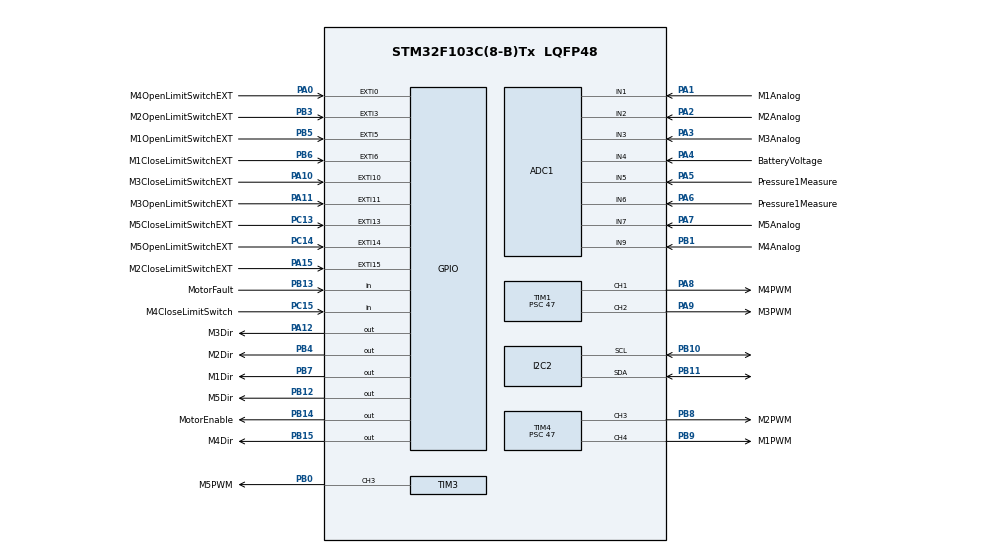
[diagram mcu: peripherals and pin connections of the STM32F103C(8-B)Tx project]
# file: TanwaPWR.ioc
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ADC1.Channel-0\#ChannelRegularConversion=ADC_CHANNEL_1
ADC1.Channel-1\#ChannelRegularConversion=ADC_CHANNEL_2
ADC1.Channel-2\#ChannelRegularConversion=ADC_CHANNEL_3
ADC1.Channel-3\#ChannelRegularConversion=ADC_CHANNEL_4
ADC1.Channel-4\#ChannelRegularConversion=ADC_CHANNEL_5
ADC1.Channel-5\#ChannelRegularConversion=ADC_CHANNEL_6
ADC1.Channel-6\#ChannelRegularConversion=ADC_CHANNEL_7
ADC1.Channel-7\#ChannelRegularConversion=ADC_CHANNEL_9
ADC1.ContinuousConvMode=ENABLE
ADC1.DiscontinuousConvMode=DISABLE
ADC1.NbrOfConversion=8
ADC1.NbrOfConversionFlag=1
ADC1.Rank-0\#ChannelRegularConversion=1
ADC1.Rank-1\#ChannelRegularConversion=2
ADC1.Rank-2\#ChannelRegularConversion=3
ADC1.Rank-3\#ChannelRegularConversion=4
ADC1.Rank-4\#ChannelRegularConversion=5
ADC1.Rank-5\#ChannelRegularConversion=6
ADC1.Rank-6\#ChannelRegularConversion=7
ADC1.Rank-7\#ChannelRegularConversion=8
ADC1.SamplingTime-0\#ChannelRegularConversion=ADC_SAMPLETIME_28CYCLES_5
ADC1.SamplingTime-1\#ChannelRegularConversion=ADC_SAMPLETIME_28CYCLES_5
ADC1.SamplingTime-2\#ChannelRegularConversion=ADC_SAMPLETIME_28CYCLES_5
ADC1.SamplingTime-3\#ChannelRegularConversion=ADC_SAMPLETIME_28CYCLES_5
ADC1.SamplingTime-4\#ChannelRegularConversion=ADC_SAMPLETIME_28CYCLES_5
ADC1.SamplingTime-5\#ChannelRegularConversion=ADC_SAMPLETIME_28CYCLES_5
ADC1.SamplingTime-6\#ChannelRegularConversion=ADC_SAMPLETIME_28CYCLES_5
ADC1.SamplingTime-7\#ChannelRegularConversion=ADC_SAMPLETIME_28CYCLES_5
ADC1.master=1
Dma.ADC1.1.Direction=DMA_PERIPH_TO_MEMORY
Dma.ADC1.1.Instance=DMA1_Channel1
Dma.ADC1.1.MemDataAlignment=DMA_MDATAALIGN_HALFWORD
Dma.ADC1.1.MemInc=DMA_MINC_ENABLE
Dma.ADC1.1.Mode=DMA_CIRCULAR
Dma.ADC1.1.PeriphDataAlignment=DMA_PDATAALIGN_HALFWORD
Dma.ADC1.1.PeriphInc=DMA_PINC_DISABLE
Dma.ADC1.1.Priority=DMA_PRIORITY_MEDIUM
Dma.I2C2_TX.0.Direction=DMA_MEMORY_TO_PERIPH
Dma.I2C2_TX.0.Instance=DMA1_Channel4
Dma.I2C2_TX.0.MemDataAlignment=DMA_MDATAALIGN_BYTE
Dma.I2C2_TX.0.MemInc=DMA_MINC_ENABLE
Dma.I2C2_TX.0.Mode=DMA_NORMAL
Dma.I2C2_TX.0.PeriphDataAlignment=DMA_PDATAALIGN_BYTE
Dma.I2C2_TX.0.PeriphInc=DMA_PINC_DISABLE
Dma.I2C2_TX.0.Priority=DMA_PRIORITY_HIGH
Dma.Request0=I2C2_TX
Dma.Request1=ADC1
FREERTOS.Tasks01=COM,24,128,TaskCOM,Default,NULL,Dynamic,NULL,NULL;Valves,16,128,TaskValves,Default,NULL,Dynamic,NULL,NULL;Measure,8,128,TaskMeasure,Default,NULL,Dynamic,NULL,NULL
FREERTOS.configUSE_NEWLIB_REENTRANT=0
I2C2.OwnAddress=26
Mcu.Family=STM32F1
Mcu.Name=STM32F103C(8-B)Tx
Mcu.Package=LQFP48
NVIC.DMA1_Channel1_IRQn=true\:5\:0\:false\:false\:true\:true\:false\:true
NVIC.DMA1_Channel4_IRQn=true\:5\:0\:false\:false\:true\:true\:false\:true
NVIC.EXTI15_10_IRQn=true\:5\:0\:false\:false\:true\:true\:true\:true
NVIC.EXTI3_IRQn=true\:5\:0\:false\:false\:true\:true\:true\:true
NVIC.EXTI9_5_IRQn=true\:5\:0\:false\:false\:true\:true\:true\:true
NVIC.I2C2_EV_IRQn=true\:5\:0\:false\:false\:true\:true\:true\:true
NVIC.PriorityGroup=NVIC_PRIORITYGROUP_4
NVIC.TIM2_IRQn=true\:15\:0\:false\:false\:true\:false\:false\:true
NVIC.TimeBase=TIM2_IRQn
NVIC.TimeBaseIP=TIM2
PA0-WKUP.GPIO_Label=M4OpenLimitSwitchEXT
PA0-WKUP.GPIO_ModeDefaultEXTI=GPIO_MODE_IT_FALLING
PA0-WKUP.GPIO_PuPd=GPIO_PULLUP
PA0-WKUP.Signal=GPXTI0
PA1.GPIO_Label=M1Analog
PA1.Signal=ADCx_IN1
PA10.GPIO_Label=M3CloseLimitSwitchEXT
PA10.GPIO_ModeDefaultEXTI=GPIO_MODE_IT_FALLING
PA10.GPIO_PuPd=GPIO_PULLUP
PA10.Signal=GPXTI10
PA11.GPIO_Label=M3OpenLimitSwitchEXT
PA11.GPIO_ModeDefaultEXTI=GPIO_MODE_IT_FALLING
PA11.GPIO_PuPd=GPIO_PULLUP
PA11.Signal=GPXTI11
PA12.GPIO_Label=M3Dir
PA12.Signal=GPIO_Output
PA13.Mode=Serial_Wire
PA13.Signal=SYS_JTMS-SWDIO
PA14.Mode=Serial_Wire
PA14.Signal=SYS_JTCK-SWCLK
PA15.GPIO_Label=M2CloseLimitSwitchEXT
PA15.GPIO_ModeDefaultEXTI=GPIO_MODE_IT_FALLING
PA15.GPIO_PuPd=GPIO_PULLUP
PA15.Signal=GPXTI15
PA2.GPIO_Label=M2Analog
PA2.Signal=ADCx_IN2
PA3.GPIO_Label=M3Analog
PA3.Signal=ADCx_IN3
PA4.GPIO_Label=BatteryVoltage
PA4.Signal=ADCx_IN4
PA5.GPIO_Label=Pressure1Measure
PA5.Signal=ADCx_IN5
PA6.GPIO_Label=Pressure1Measure
PA6.Signal=ADCx_IN6
PA7.GPIO_Label=M5Analog
PA7.Signal=ADCx_IN7
PA8.GPIO_Label=M4PWM
PA8.Signal=S_TIM1_CH1
PA9.GPIO_Label=M3PWM
PA9.Signal=S_TIM1_CH2
PB0.GPIO_Label=M5PWM
PB0.Signal=S_TIM3_CH3
PB1.GPIO_Label=M4Analog
PB1.Signal=ADCx_IN9
PB10.Mode=I2C
PB10.Signal=I2C2_SCL
PB11.Mode=I2C
PB11.Signal=I2C2_SDA
PB12.GPIO_Label=M5Dir
PB12.Signal=GPIO_Output
PB13.GPIO_Label=MotorFault
PB13.Signal=GPIO_Input
PB14.GPIO_Label=MotorEnable
PB14.GPIO_PuPd=GPIO_NOPULL
PB14.Signal=GPIO_Output
PB15.GPIO_Label=M4Dir
PB15.Signal=GPIO_Output
PB3.GPIO_Label=M2OpenLimitSwitchEXT
PB3.GPIO_ModeDefaultEXTI=GPIO_MODE_IT_FALLING
PB3.GPIO_PuPd=GPIO_PULLUP
PB3.Signal=GPXTI3
PB4.GPIO_Label=M2Dir
PB4.Signal=GPIO_Output
PB5.GPIO_Label=M1OpenLimitSwitchEXT
PB5.GPIO_ModeDefaultEXTI=GPIO_MODE_IT_FALLING
PB5.GPIO_PuPd=GPIO_PULLUP
PB5.Signal=GPXTI5
PB6.GPIO_Label=M1CloseLimitSwitchEXT
PB6.GPIO_ModeDefaultEXTI=GPIO_MODE_IT_FALLING
PB6.GPIO_PuPd=GPIO_PULLUP
PB6.Signal=GPXTI6
PB7.GPIO_Label=M1Dir
PB7.Signal=GPIO_Output
PB8.GPIO_Label=M2PWM
PB8.Signal=S_TIM4_CH3
PB9.GPIO_Label=M1PWM
PB9.Signal=S_TIM4_CH4
PC13-TAMPER-RTC.GPIO_Label=M5CloseLimitSwitchEXT
PC13-TAMPER-RTC.GPIO_ModeDefaultEXTI=GPIO_MODE_IT_FALLING
PC13-TAMPER-RTC.GPIO_PuPd=GPIO_PULLUP
PC13-TAMPER-RTC.Signal=GPXTI13
PC14-OSC32_IN.GPIO_Label=M5OpenLimitSwitchEXT
PC14-OSC32_IN.GPIO_ModeDefaultEXTI=GPIO_MODE_IT_FALLING
PC14-OSC32_IN.GPIO_PuPd=GPIO_PULLUP
PC14-OSC32_IN.Signal=GPXTI14
PC15-OSC32_OUT.GPIO_Label=M4CloseLimitSwitch
PC15-OSC32_OUT.GPIO_PuPd=GPIO_PULLUP
PC15-OSC32_OUT.Signal=GPIO_Input
PD0-OSC_IN.Mode=HSE-External-Oscillator
PD0-OSC_IN.Signal=RCC_OSC_IN
PD1-OSC_OUT.Mode=HSE-External-Oscillator
PD1-OSC_OUT.Signal=RCC_OSC_OUT
ProjectManager.HeapSize=0x200
ProjectManager.StackSize=0x400
ProjectManager.TargetToolchain=STM32CubeIDE
RCC.ADCPresc=RCC_ADCPCLK2_DIV4
RCC.AHBFreq_Value=48000000
RCC.APB1CLKDivider=RCC_HCLK_DIV2
RCC.APB1Freq_Value=24000000
RCC.APB1TimFreq_Value=48000000
RCC.APB2CLKDivider=RCC_HCLK_DIV2
RCC.APB2Freq_Value=24000000
RCC.APB2TimFreq_Value=48000000
RCC.HCLKFreq_Value=48000000
RCC.PLLMUL=RCC_PLL_MUL6
RCC.PLLSourceVirtual=RCC_PLLSOURCE_HSE
RCC.SYSCLKFreq_VALUE=48000000
RCC.SYSCLKSource=RCC_SYSCLKSOURCE_PLLCLK
RCC.USBFreq_Value=48000000
SH.ADCx_IN1.0=ADC1_IN1,IN1
SH.ADCx_IN2.0=ADC1_IN2,IN2
SH.ADCx_IN3.0=ADC1_IN3,IN3
SH.ADCx_IN4.0=ADC1_IN4,IN4
SH.ADCx_IN5.0=ADC1_IN5,IN5
SH.ADCx_IN6.0=ADC1_IN6,IN6
SH.ADCx_IN7.0=ADC1_IN7,IN7
SH.ADCx_IN9.0=ADC1_IN9,IN9
SH.S_TIM1_CH1.0=TIM1_CH1,PWM Generation1 CH1
SH.S_TIM1_CH2.0=TIM1_CH2,PWM Generation2 CH2
SH.S_TIM3_CH3.0=TIM3_CH3,PWM Generation3 CH3
SH.S_TIM4_CH3.0=TIM4_CH3,PWM Generation3 CH3
SH.S_TIM4_CH4.0=TIM4_CH4,PWM Generation4 CH4
TIM1.AutoReloadPreload=TIM_AUTORELOAD_PRELOAD_ENABLE
TIM1.Channel-PWM\ Generation1\ CH1=TIM_CHANNEL_1
TIM1.Channel-PWM\ Generation2\ CH2=TIM_CHANNEL_2
TIM1.OCMode_PWM-PWM\ Generation2\ CH2=TIM_OCMODE_PWM1
TIM1.Period=999
TIM1.Prescaler=47
TIM1.Pulse-PWM\ Generation1\ CH1=1000
TIM1.Pulse-PWM\ Generation2\ CH2=1000
TIM3.AutoReloadPreload=TIM_AUTORELOAD_PRELOAD_ENABLE
TIM3.Channel-PWM\ Generation3\ CH3=TIM_CHANNEL_3
TIM3.Period=999
TIM3.Prescaler=47
TIM3.Pulse-PWM\ Generation3\ CH3=1000
TIM4.AutoReloadPreload=TIM_AUTORELOAD_PRELOAD_ENABLE
TIM4.Channel-PWM\ Generation3\ CH3=TIM_CHANNEL_3
TIM4.Channel-PWM\ Generation4\ CH4=TIM_CHANNEL_4
TIM4.Period=999
TIM4.Prescaler=47
TIM4.Pulse-PWM\ Generation3\ CH3=1000
TIM4.Pulse-PWM\ Generation4\ CH4=1000
VP_FREERTOS_VS_CMSIS_V2.Mode=CMSIS_V2
VP_SYS_VS_tim2.Mode=TIM2
board=custom

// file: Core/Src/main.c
/* USER CODE BEGIN Header */
/**
  ******************************************************************************
  * @file           : main.c
  * @brief          : Main program body
  ******************************************************************************
  * @attention
  *
  * Copyright (c) 2022 STMicroelectronics.
  * All rights reserved.
  *
  * This software is licensed under terms that can be found in the LICENSE file
  * in the root directory of this software component.
  * If no LICENSE file comes with this software, it is provided AS-IS.
  *
  ******************************************************************************
  */
/* USER CODE END Header */
#include "main.h"
#include "cmsis_os.h"

ADC_HandleTypeDef hadc1;

I2C_HandleTypeDef hi2c2;

TIM_HandleTypeDef htim1;
TIM_HandleTypeDef htim3;
TIM_HandleTypeDef htim4;

/* Definitions for defaultTask */
osThreadId_t defaultTaskHandle;
const osThreadAttr_t defaultTask_attributes = {
  .name = "defaultTask",
  .stack_size = 128 * 4,
  .priority = (osPriority_t) osPriorityNormal,
};
/* Definitions for myTask02 */
osThreadId_t myTask02Handle;
const osThreadAttr_t myTask02_attributes = {
  .name = "myTask02",
  .stack_size = 128 * 4,
  .priority = (osPriority_t) osPriorityLow,
};

void SystemClock_Config(void);
static void MX_GPIO_Init(void);
static void MX_ADC1_Init(void);
static void MX_I2C2_Init(void);
static void MX_TIM1_Init(void);
static void MX_TIM3_Init(void);
static void MX_TIM4_Init(void);
void StartDefaultTask(void *argument);
void StartTask02(void *argument);

int main(void)
{

  /* MCU Configuration--------------------------------------------------------*/

  /* Reset of all peripherals, Initializes the Flash interface and the Systick. */
  HAL_Init();

  /* Configure the system clock */
  SystemClock_Config();

  /* Initialize all configured peripherals */
  MX_GPIO_Init();
  MX_ADC1_Init();
  MX_I2C2_Init();
  MX_TIM1_Init();
  MX_TIM3_Init();
  MX_TIM4_Init();

  /* Init scheduler */
  osKernelInitialize();

  /* Create the thread(s) */
  /* creation of defaultTask */
  defaultTaskHandle = osThreadNew(StartDefaultTask, NULL, &defaultTask_attributes);

  /* creation of myTask02 */
  myTask02Handle = osThreadNew(StartTask02, NULL, &myTask02_attributes);

  /* Start scheduler */
  osKernelStart();

  /* We should never get here as control is now taken by the scheduler */
  /* Infinite loop */
  while (1)
  {

  }
}

void SystemClock_Config(void)
{
  RCC_OscInitTypeDef RCC_OscInitStruct = {0};
  RCC_ClkInitTypeDef RCC_ClkInitStruct = {0};
  RCC_PeriphCLKInitTypeDef PeriphClkInit = {0};

  /** Initializes the RCC Oscillators according to the specified parameters
  * in the RCC_OscInitTypeDef structure.
  */
  RCC_OscInitStruct.OscillatorType = RCC_OSCILLATORTYPE_HSI;
  RCC_OscInitStruct.HSIState = RCC_HSI_ON;
  RCC_OscInitStruct.HSICalibrationValue = RCC_HSICALIBRATION_DEFAULT;
  RCC_OscInitStruct.PLL.PLLState = RCC_PLL_NONE;
  if (HAL_RCC_OscConfig(&RCC_OscInitStruct) != HAL_OK)
  {
    Error_Handler();
  }
  /** Initializes the CPU, AHB and APB buses clocks
  */
  RCC_ClkInitStruct.ClockType = RCC_CLOCKTYPE_HCLK|RCC_CLOCKTYPE_SYSCLK
                              |RCC_CLOCKTYPE_PCLK1|RCC_CLOCKTYPE_PCLK2;
  RCC_ClkInitStruct.SYSCLKSource = RCC_SYSCLKSOURCE_HSI;
  RCC_ClkInitStruct.AHBCLKDivider = RCC_SYSCLK_DIV1;
  RCC_ClkInitStruct.APB1CLKDivider = RCC_HCLK_DIV1;
  RCC_ClkInitStruct.APB2CLKDivider = RCC_HCLK_DIV1;

  if (HAL_RCC_ClockConfig(&RCC_ClkInitStruct, FLASH_LATENCY_0) != HAL_OK)
  {
    Error_Handler();
  }
  PeriphClkInit.PeriphClockSelection = RCC_PERIPHCLK_ADC;
  PeriphClkInit.AdcClockSelection = RCC_ADCPCLK2_DIV2;
  if (HAL_RCCEx_PeriphCLKConfig(&PeriphClkInit) != HAL_OK)
  {
    Error_Handler();
  }
}

static void MX_ADC1_Init(void)
{

  ADC_ChannelConfTypeDef sConfig = {0};

  /** Common config
  */
  hadc1.Instance = ADC1;
  hadc1.Init.ScanConvMode = ADC_SCAN_DISABLE;
  hadc1.Init.ContinuousConvMode = DISABLE;
  hadc1.Init.DiscontinuousConvMode = DISABLE;
  hadc1.Init.ExternalTrigConv = ADC_SOFTWARE_START;
  hadc1.Init.DataAlign = ADC_DATAALIGN_RIGHT;
  hadc1.Init.NbrOfConversion = 1;
  if (HAL_ADC_Init(&hadc1) != HAL_OK)
  {
    Error_Handler();
  }
  /** Configure Regular Channel
  */
  sConfig.Channel = ADC_CHANNEL_1;
  sConfig.Rank = ADC_REGULAR_RANK_1;
  sConfig.SamplingTime = ADC_SAMPLETIME_1CYCLE_5;
  if (HAL_ADC_ConfigChannel(&hadc1, &sConfig) != HAL_OK)
  {
    Error_Handler();
  }

}

static void MX_I2C2_Init(void)
{

  hi2c2.Instance = I2C2;
  hi2c2.Init.ClockSpeed = 100000;
  hi2c2.Init.DutyCycle = I2C_DUTYCYCLE_2;
  hi2c2.Init.OwnAddress1 = 0;
  hi2c2.Init.AddressingMode = I2C_ADDRESSINGMODE_7BIT;
  hi2c2.Init.DualAddressMode = I2C_DUALADDRESS_DISABLE;
  hi2c2.Init.OwnAddress2 = 0;
  hi2c2.Init.GeneralCallMode = I2C_GENERALCALL_DISABLE;
  hi2c2.Init.NoStretchMode = I2C_NOSTRETCH_DISABLE;
  if (HAL_I2C_Init(&hi2c2) != HAL_OK)
  {
    Error_Handler();
  }

}

static void MX_TIM1_Init(void)
{

  TIM_MasterConfigTypeDef sMasterConfig = {0};
  TIM_OC_InitTypeDef sConfigOC = {0};
  TIM_BreakDeadTimeConfigTypeDef sBreakDeadTimeConfig = {0};

  htim1.Instance = TIM1;
  htim1.Init.Prescaler = 0;
  htim1.Init.CounterMode = TIM_COUNTERMODE_UP;
  htim1.Init.Period = 65535;
  htim1.Init.ClockDivision = TIM_CLOCKDIVISION_DIV1;
  htim1.Init.RepetitionCounter = 0;
  htim1.Init.AutoReloadPreload = TIM_AUTORELOAD_PRELOAD_DISABLE;
  if (HAL_TIM_PWM_Init(&htim1) != HAL_OK)
  {
    Error_Handler();
  }
  sMasterConfig.MasterOutputTrigger = TIM_TRGO_RESET;
  sMasterConfig.MasterSlaveMode = TIM_MASTERSLAVEMODE_DISABLE;
  if (HAL_TIMEx_MasterConfigSynchronization(&htim1, &sMasterConfig) != HAL_OK)
  {
    Error_Handler();
  }
  sConfigOC.OCMode = TIM_OCMODE_PWM1;
  sConfigOC.Pulse = 0;
  sConfigOC.OCPolarity = TIM_OCPOLARITY_HIGH;
  sConfigOC.OCNPolarity = TIM_OCNPOLARITY_HIGH;
  sConfigOC.OCFastMode = TIM_OCFAST_DISABLE;
  sConfigOC.OCIdleState = TIM_OCIDLESTATE_RESET;
  sConfigOC.OCNIdleState = TIM_OCNIDLESTATE_RESET;
  if (HAL_TIM_PWM_ConfigChannel(&htim1, &sConfigOC, TIM_CHANNEL_1) != HAL_OK)
  {
    Error_Handler();
  }
  if (HAL_TIM_PWM_ConfigChannel(&htim1, &sConfigOC, TIM_CHANNEL_2) != HAL_OK)
  {
    Error_Handler();
  }
  sBreakDeadTimeConfig.OffStateRunMode = TIM_OSSR_DISABLE;
  sBreakDeadTimeConfig.OffStateIDLEMode = TIM_OSSI_DISABLE;
  sBreakDeadTimeConfig.LockLevel = TIM_LOCKLEVEL_OFF;
  sBreakDeadTimeConfig.DeadTime = 0;
  sBreakDeadTimeConfig.BreakState = TIM_BREAK_DISABLE;
  sBreakDeadTimeConfig.BreakPolarity = TIM_BREAKPOLARITY_HIGH;
  sBreakDeadTimeConfig.AutomaticOutput = TIM_AUTOMATICOUTPUT_DISABLE;
  if (HAL_TIMEx_ConfigBreakDeadTime(&htim1, &sBreakDeadTimeConfig) != HAL_OK)
  {
    Error_Handler();
  }
  HAL_TIM_MspPostInit(&htim1);

}

static void MX_TIM3_Init(void)
{

  TIM_MasterConfigTypeDef sMasterConfig = {0};
  TIM_OC_InitTypeDef sConfigOC = {0};

  htim3.Instance = TIM3;
  htim3.Init.Prescaler = 0;
  htim3.Init.CounterMode = TIM_COUNTERMODE_UP;
  htim3.Init.Period = 65535;
  htim3.Init.ClockDivision = TIM_CLOCKDIVISION_DIV1;
  htim3.Init.AutoReloadPreload = TIM_AUTORELOAD_PRELOAD_DISABLE;
  if (HAL_TIM_PWM_Init(&htim3) != HAL_OK)
  {
    Error_Handler();
  }
  sMasterConfig.MasterOutputTrigger = TIM_TRGO_RESET;
  sMasterConfig.MasterSlaveMode = TIM_MASTERSLAVEMODE_DISABLE;
  if (HAL_TIMEx_MasterConfigSynchronization(&htim3, &sMasterConfig) != HAL_OK)
  {
    Error_Handler();
  }
  sConfigOC.OCMode = TIM_OCMODE_PWM1;
  sConfigOC.Pulse = 0;
  sConfigOC.OCPolarity = TIM_OCPOLARITY_HIGH;
  sConfigOC.OCFastMode = TIM_OCFAST_DISABLE;
  if (HAL_TIM_PWM_ConfigChannel(&htim3, &sConfigOC, TIM_CHANNEL_3) != HAL_OK)
  {
    Error_Handler();
  }
  HAL_TIM_MspPostInit(&htim3);

}

static void MX_TIM4_Init(void)
{

  TIM_MasterConfigTypeDef sMasterConfig = {0};
  TIM_OC_InitTypeDef sConfigOC = {0};

  htim4.Instance = TIM4;
  htim4.Init.Prescaler = 0;
  htim4.Init.CounterMode = TIM_COUNTERMODE_UP;
  htim4.Init.Period = 65535;
  htim4.Init.ClockDivision = TIM_CLOCKDIVISION_DIV1;
  htim4.Init.AutoReloadPreload = TIM_AUTORELOAD_PRELOAD_DISABLE;
  if (HAL_TIM_PWM_Init(&htim4) != HAL_OK)
  {
    Error_Handler();
  }
  sMasterConfig.MasterOutputTrigger = TIM_TRGO_RESET;
  sMasterConfig.MasterSlaveMode = TIM_MASTERSLAVEMODE_DISABLE;
  if (HAL_TIMEx_MasterConfigSynchronization(&htim4, &sMasterConfig) != HAL_OK)
  {
    Error_Handler();
  }
  sConfigOC.OCMode = TIM_OCMODE_PWM1;
  sConfigOC.Pulse = 0;
  sConfigOC.OCPolarity = TIM_OCPOLARITY_HIGH;
  sConfigOC.OCFastMode = TIM_OCFAST_DISABLE;
  if (HAL_TIM_PWM_ConfigChannel(&htim4, &sConfigOC, TIM_CHANNEL_3) != HAL_OK)
  {
    Error_Handler();
  }
  if (HAL_TIM_PWM_ConfigChannel(&htim4, &sConfigOC, TIM_CHANNEL_4) != HAL_OK)
  {
    Error_Handler();
  }
  HAL_TIM_MspPostInit(&htim4);

}

static void MX_GPIO_Init(void)
{
  GPIO_InitTypeDef GPIO_InitStruct = {0};

  /* GPIO Ports Clock Enable */
  __HAL_RCC_GPIOC_CLK_ENABLE();
  __HAL_RCC_GPIOD_CLK_ENABLE();
  __HAL_RCC_GPIOA_CLK_ENABLE();
  __HAL_RCC_GPIOB_CLK_ENABLE();

  /*Configure GPIO pin Output Level */
  HAL_GPIO_WritePin(GPIOB, M5Dir_Pin|MotorEnable_Pin|M4Dir_Pin|M2Dir_Pin
                          |M1Dir_Pin, GPIO_PIN_RESET);

  /*Configure GPIO pin Output Level */
  HAL_GPIO_WritePin(M3Dir_GPIO_Port, M3Dir_Pin, GPIO_PIN_RESET);

  /*Configure GPIO pins : M5CloseLimitSwitchEXT_Pin M5OpenLimitSwitchEXT_Pin */
  GPIO_InitStruct.Pin = M5CloseLimitSwitchEXT_Pin|M5OpenLimitSwitchEXT_Pin;
  GPIO_InitStruct.Mode = GPIO_MODE_IT_RISING;
  GPIO_InitStruct.Pull = GPIO_NOPULL;
  HAL_GPIO_Init(GPIOC, &GPIO_InitStruct);

  /*Configure GPIO pin : M4CloseLimitSwitch_Pin */
  GPIO_InitStruct.Pin = M4CloseLimitSwitch_Pin;
  GPIO_InitStruct.Mode = GPIO_MODE_INPUT;
  GPIO_InitStruct.Pull = GPIO_NOPULL;
  HAL_GPIO_Init(M4CloseLimitSwitch_GPIO_Port, &GPIO_InitStruct);

  /*Configure GPIO pin : M4OpenLimitSwitchEXT_Pin */
  GPIO_InitStruct.Pin = M4OpenLimitSwitchEXT_Pin;
  GPIO_InitStruct.Mode = GPIO_MODE_INPUT;
  GPIO_InitStruct.Pull = GPIO_NOPULL;
  HAL_GPIO_Init(M4OpenLimitSwitchEXT_GPIO_Port, &GPIO_InitStruct);

  /*Configure GPIO pins : M5Dir_Pin MotorEnable_Pin M4Dir_Pin M2Dir_Pin
                           M1Dir_Pin */
  GPIO_InitStruct.Pin = M5Dir_Pin|MotorEnable_Pin|M4Dir_Pin|M2Dir_Pin
                          |M1Dir_Pin;
  GPIO_InitStruct.Mode = GPIO_MODE_OUTPUT_PP;
  GPIO_InitStruct.Pull = GPIO_NOPULL;
  GPIO_InitStruct.Speed = GPIO_SPEED_FREQ_LOW;
  HAL_GPIO_Init(GPIOB, &GPIO_InitStruct);

  /*Configure GPIO pin : MotorFault_Pin */
  GPIO_InitStruct.Pin = MotorFault_Pin;
  GPIO_InitStruct.Mode = GPIO_MODE_INPUT;
  GPIO_InitStruct.Pull = GPIO_NOPULL;
  HAL_GPIO_Init(MotorFault_GPIO_Port, &GPIO_InitStruct);

  /*Configure GPIO pins : M3CloseLimitSwitchEXT_Pin M3OpenLimitSwitchEXT_Pin M2CloseLimitSwitchEXT_Pin */
  GPIO_InitStruct.Pin = M3CloseLimitSwitchEXT_Pin|M3OpenLimitSwitchEXT_Pin|M2CloseLimitSwitchEXT_Pin;
  GPIO_InitStruct.Mode = GPIO_MODE_IT_RISING;
  GPIO_InitStruct.Pull = GPIO_NOPULL;
  HAL_GPIO_Init(GPIOA, &GPIO_InitStruct);

  /*Configure GPIO pin : M3Dir_Pin */
  GPIO_InitStruct.Pin = M3Dir_Pin;
  GPIO_InitStruct.Mode = GPIO_MODE_OUTPUT_PP;
  GPIO_InitStruct.Pull = GPIO_NOPULL;
  GPIO_InitStruct.Speed = GPIO_SPEED_FREQ_LOW;
  HAL_GPIO_Init(M3Dir_GPIO_Port, &GPIO_InitStruct);

  /*Configure GPIO pins : M2OpenLimitSwitchEXT_Pin M1OpenLimitSwitchEXT_Pin M1CloseLimitSwitchEXT_Pin */
  GPIO_InitStruct.Pin = M2OpenLimitSwitchEXT_Pin|M1OpenLimitSwitchEXT_Pin|M1CloseLimitSwitchEXT_Pin;
  GPIO_InitStruct.Mode = GPIO_MODE_IT_RISING;
  GPIO_InitStruct.Pull = GPIO_NOPULL;
  HAL_GPIO_Init(GPIOB, &GPIO_InitStruct);

  /* EXTI interrupt init*/
  HAL_NVIC_SetPriority(EXTI3_IRQn, 5, 0);
  HAL_NVIC_EnableIRQ(EXTI3_IRQn);

  HAL_NVIC_SetPriority(EXTI9_5_IRQn, 5, 0);
  HAL_NVIC_EnableIRQ(EXTI9_5_IRQn);

  HAL_NVIC_SetPriority(EXTI15_10_IRQn, 5, 0);
  HAL_NVIC_EnableIRQ(EXTI15_10_IRQn);

}

void StartDefaultTask(void *argument)
{
  for(;;)
  {
    osDelay(1);
  }
}

void StartTask02(void *argument)
{
  for(;;)
  {
    osDelay(1);
  }
}

void HAL_TIM_PeriodElapsedCallback(TIM_HandleTypeDef *htim)
{
  if (htim->Instance == TIM2) {
    HAL_IncTick();
  }
}

void Error_Handler(void)
{
  __disable_irq();
  while (1)
  {
  }
}
